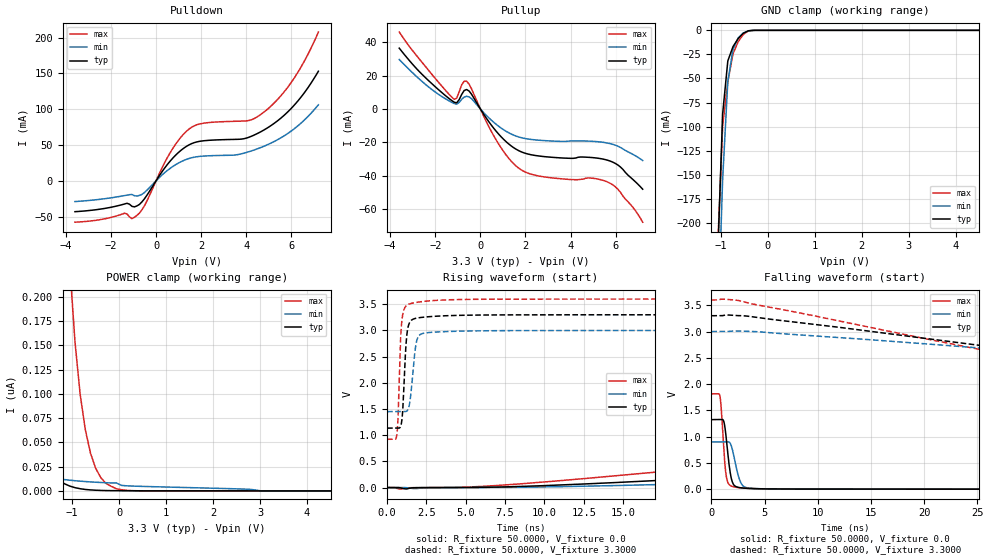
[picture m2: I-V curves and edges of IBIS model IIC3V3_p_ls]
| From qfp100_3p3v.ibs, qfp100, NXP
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[Model] IIC3V3_p_ls
|   Model IIC3V3_p_ls
| This model was characterised for following simulation conditions:
| External (pad) voltage:
|   - Typ: 3.3V,   - Min: 3.0V,   - Max: 3.6V
| Library cells for typ/min/max conditions are connected as defined below:
|  IO - External Pad
|  A - Core Input
|  EN - Output Buffer Enable
|  BOOST - vdde
|  EGP - vdd
|  EHS - gnd
|  ENZI - vdd
|  EPD - gnd
|  EPUN - vdd
|  ZI - NC
|  ZIF - NC
|  gnd - gnd
|  gnde - gnde
|  vdd - vdd
|  vdde - vdde
| All other pins connected to ground
Model_type I/O
Polarity   Non-Inverting
Enable   Active-Low
Vinl =   0.9900V
Vinh =   2.3100V
Vmeas =  1.6500V
Cref =   0.0F
Rref =   1.0000k
Vref =   0.0V
C_comp   3.6227pF   3.4779pF   3.7656pF
|C_comp_pullup   0.9287pF   0.9114pF   0.9356pF
|C_comp_pulldown   2.3426pF   2.4946pF   2.1982pF
[Model Spec]
| variable   typ   min   max
Vinh   0.9900V   0.9000V   1.0800V
Vinl   2.3100V   2.1000V   2.5200V
Vmeas   1.6500V   1.5000V   1.8000V
[Temperature Range]   25.0000   0.1250k   -40.0000
[Voltage Range]   3.3000V   3.0000V   3.6000V
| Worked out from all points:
|   slope of the pulldown table from 0 to 0.495 V, typ, clamps not added: 22 ohm
|   slope of the pullup table from 0 to 0.495 V, typ, clamps not added: 50.2 ohm
|   GND clamp passes 1 mA (typ) near -0.43 V on its own axis
|   rising waveform, R_fixture 50.0000, V_fixture 0.0: 20-80 % time 64ns typ, 78.4ns min, 50.4ns max; typ from 0 V to 1.32 V
|   rising waveform, R_fixture 50.0000, V_fixture 3.3000: 20-80 % time 227ps typ, 309ps min, 192ps max; typ from 1.14 V to 3.3 V
|   falling waveform, R_fixture 50.0000, V_fixture 0.0: 20-80 % time 465ps typ, 636ps min, 368ps max; typ from 1.32 V to 0 V
|   falling waveform, R_fixture 50.0000, V_fixture 3.3000: 20-80 % time 50.8ns typ, 68.7ns min, 38.5ns max; typ from 3.3 V to 1.14 V
[Pulldown]
|Voltage   I(typ)   I(min)   I(max)
-3.6V     -43.22mA   -29.09mA   -57.9mA
-1.29V    -31.46mA   -20.15mA   -46.47mA
-1.07V    -35.79mA   -19.19mA   -52.9mA
-850mV    -35.14mA   -21.36mA   -48.43mA
-520mV    -25.35mA   -16.52mA   -35.11mA
580mV     25.81mA    16.3mA     36.8mA
1.24V     45.79mA    28.53mA    65.82mA
1.9V      54.89mA    33.9mA     79.08mA
4.1V      60.56mA    40.39mA    84.05mA
4.76V     70.46mA    47.89mA    95.34mA
6.08V     103.9mA    71.43mA    141.2mA
7.2V      153mA      106.1mA    207.7mA
[Pullup]
|Voltage   I(typ)   I(min)   I(max)
-3.6V     36.39mA    29.61mA    46.02mA
-2.26V    16.48mA    12.77mA    22.49mA
-1.16V    4.023mA    3.267mA    5.784mA
-1.05V    3.673mA    2.839mA    6.467mA
-830mV    8.681mA    5.755mA    14.5mA
-610mV    11.63mA    7.566mA    16.61mA
710mV     -13.49mA   -9.302mA   -18.8mA
1.7V      -24.96mA   -16.76mA   -35.43mA
2.8V      -28.47mA   -18.91mA   -40.6mA
5.66V     -30.76mA   -20.46mA   -43.83mA
6.1V      -33.55mA   -22.29mA   -48.04mA
7.2V      -48.02mA   -30.86mA   -67.78mA
[GND_clamp]
|Voltage   I(typ)   I(min)   I(max)
-3.6V     -5.602A    -5.487A    -5.717A
-1.07V    -242mA     -316.8mA   -230.5mA
-960mV    -86.75mA   -154.7mA   -99.48mA
-850mV    -31.81mA   -53.08mA   -53.5mA
-740mV    -16.96mA   -19.87mA   -24.43mA
-630mV    -8.589mA   -7.919mA   -11.88mA
-520mV    -2.996mA   -2.727mA   -4.187mA
-410mV    -432.5uA   -495.8uA   -580.8uA
7.2V      0A         0A         0A
[POWER_clamp]
|Voltage   I(typ)   I(min)   I(max)
-3.6V     2.12uA     118.8nA    63.41uA
-3.03V    844.5nA    61.84nA    27.62uA
-2.37V    225.8nA    29.91nA    8.403uA
-2.04V    102.5nA    21.72nA    4.105uA
-1.82V    57.11nA    17.98nA    2.406uA
-1.49V    21.61nA    14.11nA    975.4nA
-1.05V    4.967nA    11.05nA    231.3nA
-830mV    2.261nA    10.06nA    99.54nA
-720mV    1.525nA    9.658nA    63.01nA
-500mV    718.9pA    8.985nA    23.37nA
-170mV    294.4pA    8.237nA    4.755nA
7.2V      0A         0A         0A
[Ramp]
| variable   typ   min   max
dV/dt_r  0.7941/63.9940n   0.5389/78.4223n   1.0875/50.4439n
dV/dt_f  1.2989/50.7779n   0.9297/68.6858n   1.6070/38.4858n
R_load = 50.0000
[Rising Waveform]
R_fixture= 50.0000
V_fixture= 0.0
V_fixture_min= 0.0
V_fixture_max= 0.0
|time   V(typ)   V(min)   V(max)
0s        2.243nV    52.63nV    27.54nV
860.2ps   -8.354mV   96.25uV    -30.95mV
7.694ns   14.09mV    3.106mV    53.61mV
36.07ns   426.6mV    216.4mV    777.4mV
72.53ns   857.8mV    492.3mV    1.492V
90.39ns   1.067V     599.2mV    1.672V
119.4ns   1.232V     761mV      1.77V
161.5ns   1.301V     858.8mV    1.804V
226.1ns   1.321V     892mV      1.812V
1us       1.323V     898.2mV    1.812V
[Rising Waveform]
R_fixture= 50.0000
V_fixture= 3.3000
V_fixture_min= 3.0000
V_fixture_max= 3.6000
|time   V(typ)   V(min)   V(max)
0s        1.135V     1.45V      921.7mV
623.3ps   1.135V     1.45V      1.012V
885.9ps   1.192V     1.45V      2.994V
995.6ps   1.486V     1.45V      3.308V
1.153ns   2.479V     1.449V     3.448V
1.388ns   3.122V     1.544V     3.503V
1.807ns   3.231V     2.682V     3.534V
2.03ns    3.244V     2.903V     3.544V
5.747ns   3.294V     2.993V     3.596V
1us       3.3V       3V         3.6V
[Falling Waveform]
R_fixture= 50.0000
V_fixture= 0.0
V_fixture_min= 0.0
V_fixture_max= 0.0
|time   V(typ)   V(min)   V(max)
0s        1.323V     898.3mV    1.813V
811.7ps   1.323V     898.3mV    1.764V
936.6ps   1.325V     898.3mV    1.513V
1.288ns   1.159V     898.2mV    437.6mV
1.619ns   546.6mV    900.1mV    102.8mV
2.024ns   110.5mV    713.2mV    47.69mV
2.558ns   33.4mV     237.6mV    28.48mV
2.939ns   22.04mV    70.23mV    21.07mV
5.494ns   4.545mV    4.681mV    4.711mV
1us       15.42nV    75.87nV    35.53nV
[Falling Waveform]
R_fixture= 50.0000
V_fixture= 3.3000
V_fixture_min= 3.0000
V_fixture_max= 3.6000
|time   V(typ)   V(min)   V(max)
0s        3.3V       3V         3.6V
2.441ns   3.303V     3.01V      3.594V
48.67ns   2.193V     2.354V     1.844V
54.52ns   2.077V     2.281V     1.41V
59.63ns   1.978V     2.221V     1.189V
73.24ns   1.499V     2.075V     1.003V
83.01ns   1.319V     1.96V      963mV
112.3ns   1.173V     1.577V     929mV
163.3ns   1.139V     1.467V     922.1mV
1us       1.135V     1.45V      921.7mV
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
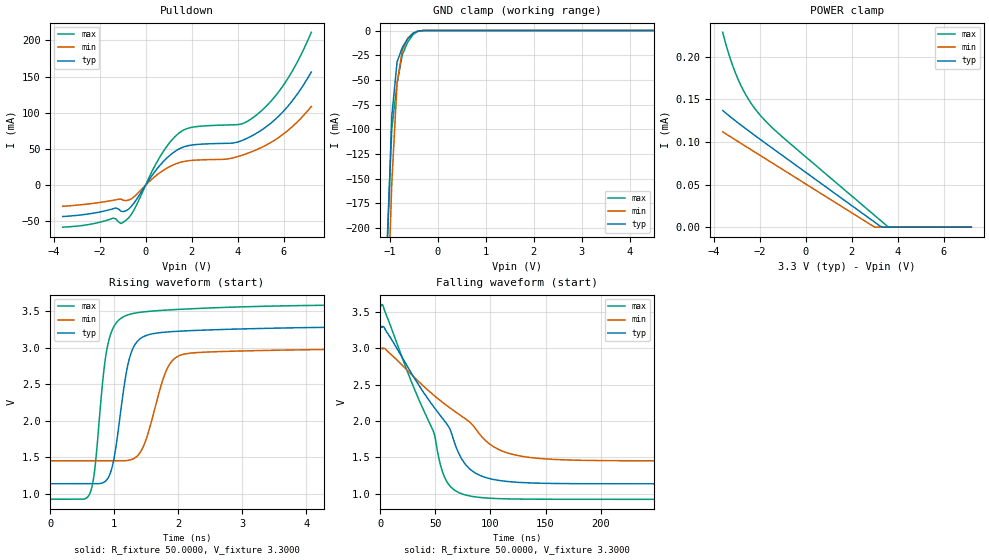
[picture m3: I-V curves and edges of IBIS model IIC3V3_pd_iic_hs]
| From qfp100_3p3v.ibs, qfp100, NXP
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[Model] IIC3V3_pd_iic_hs
|   Model IIC3V3_pd_iic_hs
| This model was characterised for following simulation conditions:
| External (pad) voltage:
|   - Typ: 3.3V,   - Min: 3.0V,   - Max: 3.6V
| Library cells for typ/min/max conditions are connected as defined below:
|  IO - External Pad
|  A - Core Input
|  EN - Output Buffer Enable
|  BOOST - vdde
|  ECS - gnd
|  EGP - gnd
|  ENZI - vdd
|  EPD - vdd
|  EPUN - vdd
|  ZI - NC
|  ZIF - NC
|  gnd - gnd
|  gnde - gnde
|  vdd - vdd
|  vdde - vdde
| All other pins connected to ground
Model_type I/O_open_drain
Polarity   Non-Inverting
Enable   Active-Low
Vinl =   0.9900V
Vinh =   2.3100V
Vmeas =  1.6500V
Cref =   0.0F
Rref =   1.0000k
Vref =   3.3000V
C_comp   3.5908pF   3.4407pF   3.7388pF
|C_comp_pullup   0.9139pF   0.9001pF   0.9174pF
|C_comp_pulldown   2.3267pF   2.4802pF   2.1806pF
[Model Spec]
| variable   typ   min   max
Vinh   0.9900V   0.9000V   1.0800V
Vinl   2.3100V   2.1000V   2.5200V
Vmeas   1.6500V   1.5000V   1.8000V
Vref   3.3000V   3.0000V   3.6000V
Cref   0.0F   0.0F   0.0F
Rref   1.0000k   1.0000k   1.0000k
[Temperature Range]   25.0000   0.1250k   -40.0000
[Voltage Range]   3.3000V   3.0000V   3.6000V
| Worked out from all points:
|   slope of the pulldown table from 0 to 0.495 V, typ, clamps not added: 22 ohm
|   GND clamp passes 1 mA (typ) near -0.43 V on its own axis
|   rising waveform, R_fixture 50.0000, V_fixture 3.3000: 20-80 % time 227ps typ, 309ps min, 193ps max; typ from 1.14 V to 3.3 V
|   falling waveform, R_fixture 50.0000, V_fixture 3.3000: 20-80 % time 50.7ns typ, 68.6ns min, 38.4ns max; typ from 3.3 V to 1.14 V
[Pulldown]
|Voltage   I(typ)   I(min)   I(max)
-3.6V     -43.22mA   -29.09mA   -57.9mA
-1.29V    -31.46mA   -20.15mA   -46.47mA
-1.07V    -35.79mA   -19.19mA   -52.9mA
-850mV    -35.14mA   -21.36mA   -48.43mA
-520mV    -25.35mA   -16.52mA   -35.11mA
580mV     25.81mA    16.3mA     36.8mA
1.24V     45.79mA    28.53mA    65.82mA
1.9V      54.89mA    33.9mA     79.08mA
4.1V      60.59mA    40.46mA    84.05mA
4.76V     70.63mA    48.16mA    95.45mA
6.08V     105.2mA    72.93mA    142.3mA
7.2V      156.3mA    108.7mA    211mA
[GND_clamp]
|Voltage   I(typ)   I(min)   I(max)
-3.6V     -5.602A    -5.487A    -5.717A
-1.07V    -242mA     -316.8mA   -230.5mA
-960mV    -86.76mA   -154.7mA   -99.49mA
-850mV    -31.82mA   -53.09mA   -53.51mA
-740mV    -16.97mA   -19.87mA   -24.44mA
-630mV    -8.597mA   -7.926mA   -11.89mA
-520mV    -3.004mA   -2.733mA   -4.196mA
-410mV    -439.7uA   -501.8uA   -589.4uA
7.2V      0A         0A         0A
[POWER_clamp]
|Voltage   I(typ)   I(min)   I(max)
-3.6V     137uA      111.9uA    228.9uA
-3.47V    134.1uA    109.7uA    215.6uA
-3.25V    129.3uA    106uA      196.2uA
-2.92V    122.3uA    100.4uA    172.9uA
-2.48V    113.3uA    92.88uA    150.2uA
-2.04V    104.5uA    85.42uA    133.7uA
-1.16V    87.2uA     70.51uA    109.7uA
2.91V     7.626uA    1.527uA    15.86uA
3.02V     5.475uA    0A         13.33uA
3.24V     1.173uA    0A         8.273uA
3.57V     0A         0A         687.1nA
7.2V      0A         0A         0A
[Ramp]
| variable   typ   min   max
dV/dt_r  1.2973/0.2266n   0.9287/0.3094n   1.6047/0.1926n
dV/dt_f  1.2973/50.7158n   0.9287/68.5865n   1.6047/38.4185n
R_load = 50.0000
[Rising Waveform]
R_fixture= 50.0000
V_fixture= 3.3000
V_fixture_min= 3.0000
V_fixture_max= 3.6000
|time   V(typ)   V(min)   V(max)
0s        1.135V     1.45V      921.3mV
627.1ps   1.134V     1.45V      1.02V
885.2ps   1.192V     1.45V      2.984V
999.3ps   1.498V     1.449V     3.302V
1.134ns   2.353V     1.449V     3.423V
1.356ns   3.086V     1.513V     3.482V
1.795ns   3.217V     2.652V     3.518V
2.027ns   3.23V      2.898V     3.53V
5.612ns   3.291V     2.989V     3.593V
1us       3.297V     2.998V     3.596V
[Falling Waveform]
R_fixture= 50.0000
V_fixture= 3.3000
V_fixture_min= 3.0000
V_fixture_max= 3.6000
|time   V(typ)   V(min)   V(max)
0s        3.297V     2.998V     3.596V
2.449ns   3.298V     2.995V     3.589V
48.58ns   2.192V     2.352V     1.841V
54.47ns   2.075V     2.279V     1.403V
59.64ns   1.974V     2.218V     1.184V
73.64ns   1.483V     2.067V     999.5mV
83.28ns   1.313V     1.951V     961.5mV
112.3ns   1.172V     1.576V     928.6mV
164ns     1.138V     1.466V     921.8mV
1us       1.135V     1.45V      921.3mV
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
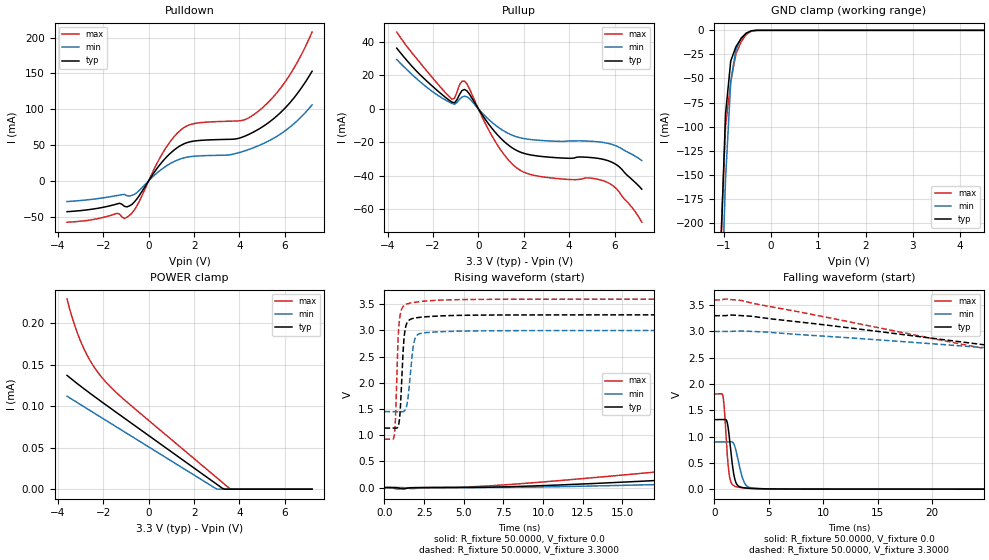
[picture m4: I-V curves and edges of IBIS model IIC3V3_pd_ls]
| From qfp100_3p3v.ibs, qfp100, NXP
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[Model] IIC3V3_pd_ls
|   Model IIC3V3_pd_ls
| This model was characterised for following simulation conditions:
| External (pad) voltage:
|   - Typ: 3.3V,   - Min: 3.0V,   - Max: 3.6V
| Library cells for typ/min/max conditions are connected as defined below:
|  IO - External Pad
|  A - Core Input
|  EN - Output Buffer Enable
|  BOOST - vdde
|  EGP - vdd
|  EHS - gnd
|  ENZI - vdd
|  EPD - vdd
|  EPUN - vdd
|  ZI - NC
|  ZIF - NC
|  gnd - gnd
|  gnde - gnde
|  vdd - vdd
|  vdde - vdde
| All other pins connected to ground
Model_type I/O
Polarity   Non-Inverting
Enable   Active-Low
Vinl =   0.9900V
Vinh =   2.3100V
Vmeas =  1.6500V
Cref =   0.0F
Rref =   1.0000k
Vref =   0.0V
C_comp   3.5907pF   3.4406pF   3.7387pF
|C_comp_pullup   0.9138pF   0.8999pF   0.9173pF
|C_comp_pulldown   2.3268pF   2.4803pF   2.1806pF
[Model Spec]
| variable   typ   min   max
Vinh   0.9900V   0.9000V   1.0800V
Vinl   2.3100V   2.1000V   2.5200V
Vmeas   1.6500V   1.5000V   1.8000V
[Temperature Range]   25.0000   0.1250k   -40.0000
[Voltage Range]   3.3000V   3.0000V   3.6000V
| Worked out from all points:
|   slope of the pulldown table from 0 to 0.495 V, typ, clamps not added: 22 ohm
|   slope of the pullup table from 0 to 0.495 V, typ, clamps not added: 50.2 ohm
|   GND clamp passes 1 mA (typ) near -0.43 V on its own axis
|   rising waveform, R_fixture 50.0000, V_fixture 0.0: 20-80 % time 64ns typ, 78.4ns min, 50.4ns max; typ from 0 V to 1.32 V
|   rising waveform, R_fixture 50.0000, V_fixture 3.3000: 20-80 % time 227ps typ, 309ps min, 192ps max; typ from 1.14 V to 3.3 V
|   falling waveform, R_fixture 50.0000, V_fixture 0.0: 20-80 % time 465ps typ, 634ps min, 367ps max; typ from 1.32 V to 0 V
|   falling waveform, R_fixture 50.0000, V_fixture 3.3000: 20-80 % time 50.8ns typ, 68.6ns min, 38.5ns max; typ from 3.3 V to 1.14 V
[Pulldown]
|Voltage   I(typ)   I(min)   I(max)
-3.6V     -43.22mA   -29.09mA   -57.9mA
-1.29V    -31.46mA   -20.15mA   -46.47mA
-1.07V    -35.79mA   -19.19mA   -52.9mA
-850mV    -35.14mA   -21.36mA   -48.43mA
-520mV    -25.35mA   -16.52mA   -35.11mA
580mV     25.81mA    16.3mA     36.8mA
1.24V     45.79mA    28.53mA    65.82mA
1.9V      54.89mA    33.9mA     79.08mA
4.1V      60.55mA    40.38mA    84.05mA
4.76V     70.44mA    47.87mA    95.32mA
6.08V     103.9mA    71.39mA    141.2mA
7.2V      152.9mA    106mA      207.6mA
[Pullup]
|Voltage   I(typ)   I(min)   I(max)
-3.6V     36.34mA    29.56mA    45.96mA
-2.26V    16.45mA    12.75mA    22.46mA
-1.16V    4.011mA    3.257mA    5.77mA
-1.05V    3.663mA    2.83mA     6.456mA
-830mV    8.674mA    5.749mA    14.49mA
-610mV    11.63mA    7.563mA    16.6mA
710mV     -13.49mA   -9.302mA   -18.8mA
1.7V      -24.96mA   -16.76mA   -35.43mA
2.8V      -28.47mA   -18.91mA   -40.6mA
5.66V     -30.76mA   -20.46mA   -43.83mA
6.1V      -33.55mA   -22.29mA   -48.04mA
7.2V      -48.02mA   -30.86mA   -67.78mA
[GND_clamp]
|Voltage   I(typ)   I(min)   I(max)
-3.6V     -5.602A    -5.487A    -5.717A
-1.07V    -242mA     -316.8mA   -230.5mA
-960mV    -86.76mA   -154.7mA   -99.49mA
-850mV    -31.82mA   -53.09mA   -53.51mA
-740mV    -16.97mA   -19.87mA   -24.44mA
-630mV    -8.597mA   -7.926mA   -11.89mA
-520mV    -3.004mA   -2.733mA   -4.196mA
-410mV    -439.7uA   -501.8uA   -589.4uA
7.2V      0A         0A         0A
[POWER_clamp]
|Voltage   I(typ)   I(min)   I(max)
-3.6V     137uA      111.9uA    228.9uA
-3.47V    134.1uA    109.7uA    215.6uA
-3.25V    129.3uA    106uA      196.2uA
-2.92V    122.3uA    100.4uA    172.9uA
-2.48V    113.3uA    92.88uA    150.2uA
-2.04V    104.5uA    85.42uA    133.7uA
-1.16V    87.2uA     70.51uA    109.7uA
2.91V     7.626uA    1.527uA    15.86uA
3.02V     5.475uA    0A         13.33uA
3.24V     1.173uA    0A         8.273uA
3.57V     0A         0A         687.1nA
7.2V      0A         0A         0A
[Ramp]
| variable   typ   min   max
dV/dt_r  0.7934/63.9635n   0.5385/78.3919n   1.0867/50.4446n
dV/dt_f  1.2983/50.7687n   0.9293/68.6224n   1.6062/38.4607n
R_load = 50.0000
[Rising Waveform]
R_fixture= 50.0000
V_fixture= 0.0
V_fixture_min= 0.0
V_fixture_max= 0.0
|time   V(typ)   V(min)   V(max)
0s        2.145nV    50.58nV    26.14nV
861.3ps   -8.453mV   96.97uV    -30.96mV
7.115ns   9.664mV    1.749mV    41.67mV
36.37ns   430.8mV    219mV      783.7mV
71.86ns   850.4mV    487.7mV    1.481V
89.51ns   1.059V     593.9mV    1.665V
118.1ns   1.228V     755.2mV    1.767V
162.1ns   1.301V     858.9mV    1.803V
227.2ns   1.32V      891.5mV    1.81V
1us       1.322V     897.5mV    1.811V
[Rising Waveform]
R_fixture= 50.0000
V_fixture= 3.3000
V_fixture_min= 3.0000
V_fixture_max= 3.6000
|time   V(typ)   V(min)   V(max)
0s        1.135V     1.45V      921.3mV
623.7ps   1.134V     1.45V      1.013V
886.3ps   1.192V     1.45V      2.995V
995.3ps   1.484V     1.449V     3.306V
1.153ns   2.478V     1.448V     3.446V
1.39ns    3.122V     1.545V     3.502V
1.808ns   3.23V      2.683V     3.532V
2.031ns   3.242V     2.902V     3.542V
5.569ns   3.291V     2.99V      3.592V
1us       3.299V     2.999V     3.598V
[Falling Waveform]
R_fixture= 50.0000
V_fixture= 0.0
V_fixture_min= 0.0
V_fixture_max= 0.0
|time   V(typ)   V(min)   V(max)
0s        1.322V     897.6mV    1.811V
803.5ps   1.322V     897.6mV    1.771V
938ps     1.323V     897.6mV    1.508V
1.29ns    1.155V     897.5mV    430.4mV
1.598ns   582.8mV    900.1mV    107.7mV
2.033ns   105.6mV    704.7mV    45.5mV
2.568ns   31.86mV    229.6mV    26.86mV
2.948ns   20.92mV    67.62mV    19.74mV
5.523ns   4.043mV    4.229mV    4.202mV
1us       15.31nV    73.81nV    34.13nV
[Falling Waveform]
R_fixture= 50.0000
V_fixture= 3.3000
V_fixture_min= 3.0000
V_fixture_max= 3.6000
|time   V(typ)   V(min)   V(max)
0s        3.299V     2.999V     3.598V
2.463ns   3.299V     3.008V     3.589V
48.43ns   2.196V     2.355V     1.851V
54.52ns   2.075V     2.279V     1.405V
59.7ns    1.974V     2.219V     1.185V
72ns      1.531V     2.085V     1.01V
83.3ns    1.314V     1.952V     961.7mV
110.8ns   1.175V     1.585V     929.2mV
168.9ns   1.137V     1.463V     921.7mV
1us       1.135V     1.45V      921.3mV
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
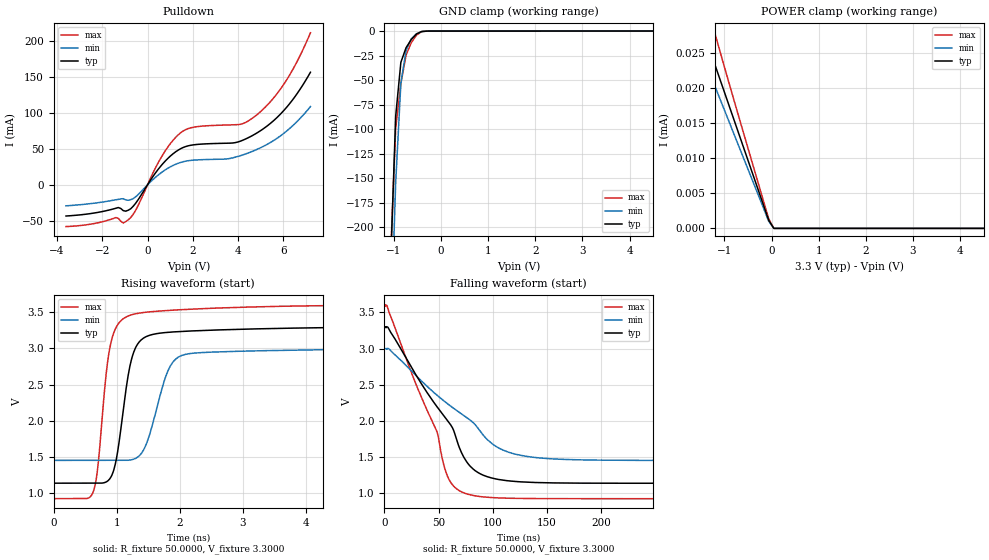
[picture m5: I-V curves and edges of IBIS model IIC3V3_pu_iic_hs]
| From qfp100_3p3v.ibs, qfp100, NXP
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[Model] IIC3V3_pu_iic_hs
|   Model IIC3V3_pu_iic_hs
| This model was characterised for following simulation conditions:
| External (pad) voltage:
|   - Typ: 3.3V,   - Min: 3.0V,   - Max: 3.6V
| Library cells for typ/min/max conditions are connected as defined below:
|  IO - External Pad
|  A - Core Input
|  EN - Output Buffer Enable
|  BOOST - vdde
|  ECS - gnd
|  EGP - gnd
|  ENZI - vdd
|  EPD - gnd
|  EPUN - gnd
|  ZI - NC
|  ZIF - NC
|  gnd - gnd
|  gnde - gnde
|  vdd - vdd
|  vdde - vdde
| All other pins connected to ground
Model_type I/O_open_drain
Polarity   Non-Inverting
Enable   Active-Low
Vinl =   0.9900V
Vinh =   2.3100V
Vmeas =  1.6500V
Cref =   0.0F
Rref =   1.0000k
Vref =   3.3000V
C_comp   3.5868pF   3.4363pF   3.7354pF
|C_comp_pullup   0.9046pF   0.8911pF   0.9077pF
|C_comp_pulldown   2.3321pF   2.4858pF   2.1859pF
[Model Spec]
| variable   typ   min   max
Vinh   0.9900V   0.9000V   1.0800V
Vinl   2.3100V   2.1000V   2.5200V
Vmeas   1.6500V   1.5000V   1.8000V
Vref   3.3000V   3.0000V   3.6000V
Cref   0.0F   0.0F   0.0F
Rref   1.0000k   1.0000k   1.0000k
[Temperature Range]   25.0000   0.1250k   -40.0000
[Voltage Range]   3.3000V   3.0000V   3.6000V
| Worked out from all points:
|   slope of the pulldown table from 0 to 0.495 V, typ, clamps not added: 22 ohm
|   GND clamp passes 1 mA (typ) near -0.43 V on its own axis
|   rising waveform, R_fixture 50.0000, V_fixture 3.3000: 20-80 % time 227ps typ, 309ps min, 193ps max; typ from 1.14 V to 3.3 V
|   falling waveform, R_fixture 50.0000, V_fixture 3.3000: 20-80 % time 50.8ns typ, 68.7ns min, 38.5ns max; typ from 3.3 V to 1.14 V
[Pulldown]
|Voltage   I(typ)   I(min)   I(max)
-3.6V     -43.22mA   -29.09mA   -57.9mA
-1.29V    -31.46mA   -20.15mA   -46.47mA
-1.07V    -35.79mA   -19.19mA   -52.9mA
-850mV    -35.14mA   -21.36mA   -48.43mA
-520mV    -25.35mA   -16.52mA   -35.11mA
580mV     25.81mA    16.3mA     36.8mA
1.24V     45.79mA    28.53mA    65.82mA
1.9V      54.89mA    33.9mA     79.08mA
4.1V      60.59mA    40.46mA    84.05mA
4.76V     70.63mA    48.16mA    95.45mA
6.08V     105.2mA    72.93mA    142.3mA
7.2V      156.3mA    108.7mA    211mA
[GND_clamp]
|Voltage   I(typ)   I(min)   I(max)
-3.6V     -5.602A    -5.487A    -5.717A
-1.07V    -242.1mA   -316.8mA   -230.6mA
-960mV    -86.82mA   -154.8mA   -99.57mA
-850mV    -31.89mA   -53.14mA   -53.6mA
-740mV    -17.03mA   -19.92mA   -24.52mA
-630mV    -8.661mA   -7.977mA   -11.97mA
-520mV    -3.068mA   -2.784mA   -4.278mA
-410mV    -504.1uA   -552.6uA   -671.9uA
7.2V      0A         0A         0A
[POWER_clamp]
|Voltage   I(typ)   I(min)   I(max)
-3.6V     71.92uA    60.65uA    145.6uA
-1.71V    33.28uA    28.87uA    40.89uA
-1.6V     31.13uA    27.02uA    37.92uA
-1.49V    28.99uA    25.16uA    35.04uA
-1.38V    26.85uA    23.31uA    32.26uA
-1.27V    24.71uA    21.46uA    29.54uA
-1.16V    22.58uA    19.61uA    26.88uA
-720mV    14.02uA    12.19uA    16.54uA
-60mV     1.171uA    1.025uA    1.377uA
50mV      0A         0A         0A
7.2V      0A         0A         0A
[Ramp]
| variable   typ   min   max
dV/dt_r  1.2984/0.2267n   0.9292/0.3093n   1.6064/0.1926n
dV/dt_f  1.2984/50.7672n   0.9292/68.6924n   1.6064/38.4880n
R_load = 50.0000
[Rising Waveform]
R_fixture= 50.0000
V_fixture= 3.3000
V_fixture_min= 3.0000
V_fixture_max= 3.6000
|time   V(typ)   V(min)   V(max)
0s        1.136V     1.451V     922.6mV
627.5ps   1.136V     1.451V     1.022V
886.2ps   1.194V     1.451V     2.993V
998.1ps   1.495V     1.451V     3.304V
1.136ns   2.371V     1.451V     3.429V
1.355ns   3.088V     1.514V     3.487V
1.817ns   3.222V     2.7V       3.524V
2.026ns   3.233V     2.9V       3.534V
5.582ns   3.295V     2.992V     3.597V
1us       3.3V       3V         3.6V
[Falling Waveform]
R_fixture= 50.0000
V_fixture= 3.3000
V_fixture_min= 3.0000
V_fixture_max= 3.6000
|time   V(typ)   V(min)   V(max)
0s        3.3V       3V         3.6V
2.455ns   3.301V     2.998V     3.592V
48.62ns   2.194V     2.354V     1.844V
54.53ns   2.076V     2.281V     1.406V
59.7ns    1.976V     2.22V      1.187V
73.1ns    1.502V     2.076V     1.004V
83.3ns    1.316V     1.955V     963.1mV
112.3ns   1.173V     1.578V     929.9mV
163.5ns   1.14V      1.468V     923.1mV
1us       1.136V     1.451V     922.6mV
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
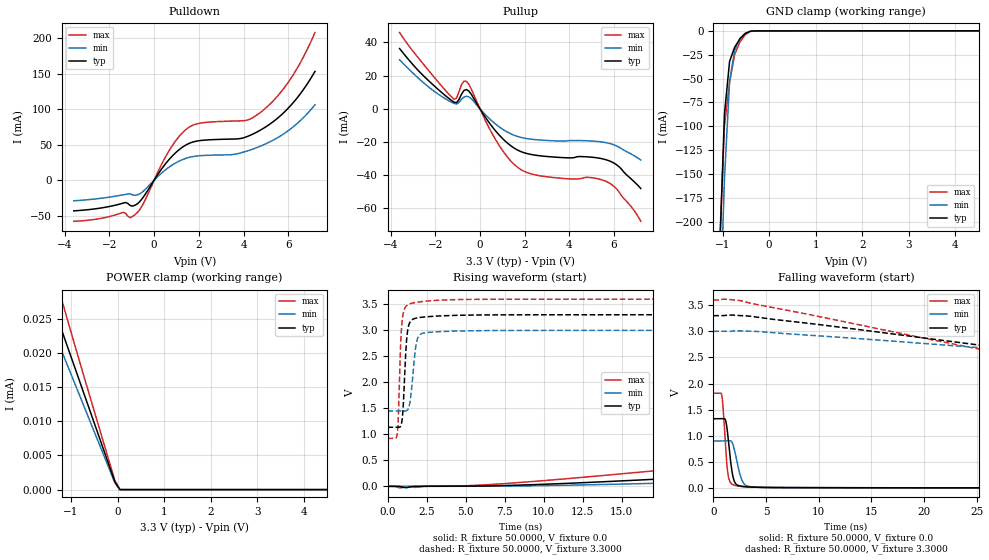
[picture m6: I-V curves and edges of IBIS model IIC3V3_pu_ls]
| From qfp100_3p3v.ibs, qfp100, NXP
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[Model] IIC3V3_pu_ls
|   Model IIC3V3_pu_ls
| This model was characterised for following simulation conditions:
| External (pad) voltage:
|   - Typ: 3.3V,   - Min: 3.0V,   - Max: 3.6V
| Library cells for typ/min/max conditions are connected as defined below:
|  IO - External Pad
|  A - Core Input
|  EN - Output Buffer Enable
|  BOOST - vdde
|  EGP - vdd
|  EHS - gnd
|  ENZI - vdd
|  EPD - gnd
|  EPUN - gnd
|  ZI - NC
|  ZIF - NC
|  gnd - gnd
|  gnde - gnde
|  vdd - vdd
|  vdde - vdde
| All other pins connected to ground
Model_type I/O
Polarity   Non-Inverting
Enable   Active-Low
Vinl =   0.9900V
Vinh =   2.3100V
Vmeas =  1.6500V
Cref =   0.0F
Rref =   1.0000k
Vref =   0.0V
C_comp   3.5867pF   3.4362pF   3.7352pF
|C_comp_pullup   0.9044pF   0.8908pF   0.9076pF
|C_comp_pulldown   2.3321pF   2.4859pF   2.1859pF
[Model Spec]
| variable   typ   min   max
Vinh   0.9900V   0.9000V   1.0800V
Vinl   2.3100V   2.1000V   2.5200V
Vmeas   1.6500V   1.5000V   1.8000V
[Temperature Range]   25.0000   0.1250k   -40.0000
[Voltage Range]   3.3000V   3.0000V   3.6000V
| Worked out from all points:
|   slope of the pulldown table from 0 to 0.495 V, typ, clamps not added: 22 ohm
|   slope of the pullup table from 0 to 0.495 V, typ, clamps not added: 50.2 ohm
|   GND clamp passes 1 mA (typ) near -0.43 V on its own axis
|   rising waveform, R_fixture 50.0000, V_fixture 0.0: 20-80 % time 64ns typ, 78.4ns min, 50.4ns max; typ from 0.001 V to 1.32 V
|   rising waveform, R_fixture 50.0000, V_fixture 3.3000: 20-80 % time 227ps typ, 309ps min, 192ps max; typ from 1.14 V to 3.3 V
|   falling waveform, R_fixture 50.0000, V_fixture 0.0: 20-80 % time 466ps typ, 636ps min, 368ps max; typ from 1.32 V to 0.001 V
|   falling waveform, R_fixture 50.0000, V_fixture 3.3000: 20-80 % time 50.8ns typ, 68.7ns min, 38.5ns max; typ from 3.3 V to 1.14 V
[Pulldown]
|Voltage   I(typ)   I(min)   I(max)
-3.6V     -43.22mA   -29.09mA   -57.9mA
-1.29V    -31.46mA   -20.15mA   -46.47mA
-1.07V    -35.79mA   -19.19mA   -52.9mA
-850mV    -35.14mA   -21.36mA   -48.43mA
-520mV    -25.35mA   -16.52mA   -35.11mA
580mV     25.81mA    16.3mA     36.8mA
1.24V     45.79mA    28.53mA    65.82mA
1.9V      54.89mA    33.9mA     79.08mA
4.1V      60.55mA    40.38mA    84.05mA
4.76V     70.44mA    47.87mA    95.32mA
6.08V     103.9mA    71.39mA    141.2mA
7.2V      152.9mA    106mA      207.6mA
[Pullup]
|Voltage   I(typ)   I(min)   I(max)
-3.6V     36.34mA    29.56mA    45.96mA
-2.26V    16.45mA    12.75mA    22.46mA
-1.16V    4.011mA    3.257mA    5.77mA
-1.05V    3.663mA    2.83mA     6.455mA
-830mV    8.673mA    5.749mA    14.49mA
-610mV    11.63mA    7.563mA    16.6mA
710mV     -13.49mA   -9.302mA   -18.8mA
1.7V      -24.96mA   -16.76mA   -35.43mA
2.8V      -28.47mA   -18.91mA   -40.6mA
5.66V     -30.76mA   -20.46mA   -43.83mA
6.1V      -33.55mA   -22.29mA   -48.04mA
7.2V      -48.02mA   -30.86mA   -67.78mA
[GND_clamp]
|Voltage   I(typ)   I(min)   I(max)
-3.6V     -5.602A    -5.487A    -5.717A
-1.07V    -242.1mA   -316.8mA   -230.6mA
-960mV    -86.82mA   -154.8mA   -99.57mA
-850mV    -31.89mA   -53.14mA   -53.6mA
-740mV    -17.03mA   -19.92mA   -24.52mA
-630mV    -8.661mA   -7.977mA   -11.97mA
-520mV    -3.068mA   -2.784mA   -4.278mA
-410mV    -504.1uA   -552.6uA   -671.9uA
7.2V      0A         0A         0A
[POWER_clamp]
|Voltage   I(typ)   I(min)   I(max)
-3.6V     71.92uA    60.65uA    145.6uA
-1.71V    33.28uA    28.87uA    40.89uA
-1.6V     31.13uA    27.02uA    37.92uA
-1.49V    28.99uA    25.16uA    35.04uA
-1.38V    26.85uA    23.31uA    32.26uA
-1.27V    24.71uA    21.46uA    29.54uA
-1.16V    22.58uA    19.61uA    26.88uA
-720mV    14.02uA    12.19uA    16.54uA
-60mV     1.171uA    1.025uA    1.377uA
50mV      0A         0A         0A
7.2V      0A         0A         0A
[Ramp]
| variable   typ   min   max
dV/dt_r  0.7945/63.9693n   0.5393/78.3973n   1.0878/50.4118n
dV/dt_f  1.2984/50.8047n   0.9292/68.6852n   1.6064/38.4897n
R_load = 50.0000
[Rising Waveform]
R_fixture= 50.0000
V_fixture= 0.0
V_fixture_min= 0.0
V_fixture_max= 0.0
|time   V(typ)   V(min)   V(max)
0s        903.5uV    965.2uV    889.6uV
860.3ps   -7.442mV   1.061mV    -28.62mV
7.683ns   17.11mV    5.617mV    57.12mV
36.03ns   428.9mV    218.5mV    780mV
72.51ns   860.4mV    494.4mV    1.495V
90.37ns   1.07V      601.4mV    1.674V
119.5ns   1.235V     763.7mV    1.772V
161.2ns   1.303V     860.2mV    1.806V
225.5ns   1.322V     893.6mV    1.813V
1us       1.325V     899.8mV    1.814V
[Rising Waveform]
R_fixture= 50.0000
V_fixture= 3.3000
V_fixture_min= 3.0000
V_fixture_max= 3.6000
|time   V(typ)   V(min)   V(max)
0s        1.136V     1.451V     922.6mV
623.3ps   1.136V     1.451V     1.014V
885.9ps   1.194V     1.451V     2.997V
995.6ps   1.488V     1.45V      3.311V
1.152ns   2.479V     1.45V      3.45V
1.388ns   3.124V     1.545V     3.506V
1.806ns   3.233V     2.682V     3.536V
2.029ns   3.245V     2.904V     3.546V
5.588ns   3.294V     2.993V     3.596V
1us       3.3V       3V         3.6V
[Falling Waveform]
R_fixture= 50.0000
V_fixture= 0.0
V_fixture_min= 0.0
V_fixture_max= 0.0
|time   V(typ)   V(min)   V(max)
0s        1.325V     899.9mV    1.814V
811.5ps   1.325V     899.9mV    1.766V
936.9ps   1.326V     899.9mV    1.514V
1.288ns   1.161V     899.8mV    439mV
1.62ns    546.3mV    901.6mV    104.6mV
2.025ns   112.1mV    714.3mV    50.05mV
2.556ns   35.58mV    240.3mV    31.23mV
2.938ns   24.31mV    72.31mV    24mV
5.516ns   7.277mV    6.772mV    8.332mV
1us       903.6uV    965.2uV    889.6uV
[Falling Waveform]
R_fixture= 50.0000
V_fixture= 3.3000
V_fixture_min= 3.0000
V_fixture_max= 3.6000
|time   V(typ)   V(min)   V(max)
0s        3.3V       3V         3.6V
2.451ns   3.303V     3.01V      3.593V
48.64ns   2.195V     2.355V     1.846V
54.55ns   2.078V     2.281V     1.409V
59.7ns    1.977V     2.221V     1.188V
73.96ns   1.48V      2.067V     1V
83.22ns   1.318V     1.957V     963.5mV
110.3ns   1.177V     1.591V     930.7mV
164.3ns   1.14V      1.467V     923.1mV
1us       1.136V     1.451V     922.6mV
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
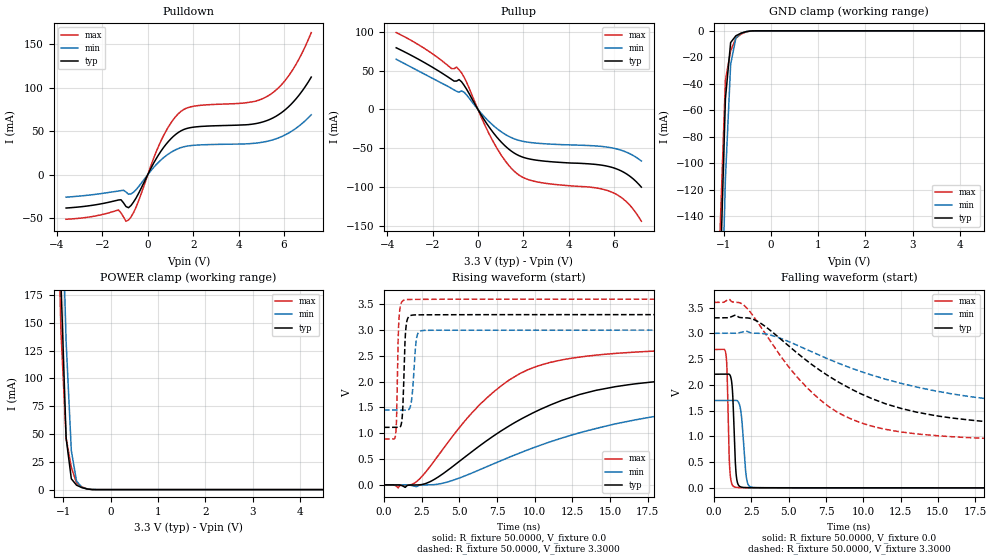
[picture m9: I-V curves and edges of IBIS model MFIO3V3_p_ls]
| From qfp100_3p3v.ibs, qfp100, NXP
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[Model] MFIO3V3_p_ls
|   Model MFIO3V3_p_ls
| This model was characterised for following simulation conditions:
| External (pad) voltage:
|   - Typ: 3.3V,   - Min: 3.0V,   - Max: 3.6V
| Library cells for typ/min/max conditions are connected as defined below:
|  IO - External Pad
|  A - Core Input
|  EN - Output Buffer Enable
|  BOOST - vdde
|  EHS - gnd
|  ENZI - vdd
|  EPD - gnd
|  EPUN - vdd
|  ZI - NC
|  ZIF - NC
|  gnd - gnd
|  gnde - gnde
|  vdd - vdd
|  vdde - vdde
| All other pins connected to ground
Model_type I/O
Polarity   Non-Inverting
Enable   Active-Low
Vinl =   0.9900V
Vinh =   2.3100V
Vmeas =  1.6500V
Cref =   0.0F
Rref =   100.0000
Vref =   0.0V
C_comp   1.5616pF   1.4857pF   1.6280pF
|C_comp_pullup   0.7424pF   0.7664pF   0.7060pF
|C_comp_pulldown   0.6045pF   0.6430pF   0.5687pF
[Model Spec]
| variable   typ   min   max
Vinh   0.9900V   0.9000V   1.0800V
Vinl   2.3100V   2.1000V   2.5200V
Vmeas   1.6500V   1.5000V   1.8000V
[Temperature Range]   25.0000   0.1250k   -40.0000
[Voltage Range]   3.3000V   3.0000V   3.6000V
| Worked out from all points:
|   slope of the pulldown table from 0 to 0.495 V, typ, clamps not added: 21 ohm
|   slope of the pullup table from 0 to 0.495 V, typ, clamps not added: 21.7 ohm
|   GND clamp passes 1 mA (typ) near -0.56 V on its own axis
|   POWER clamp passes 1 mA (typ) near -0.54 V on its own axis
|   rising waveform, R_fixture 50.0000, V_fixture 0.0: 20-80 % time 8.22ns typ, 11.9ns min, 5.44ns max; typ from 0 V to 2.21 V
|   rising waveform, R_fixture 50.0000, V_fixture 3.3000: 20-80 % time 151ps typ, 221ps min, 120ps max; typ from 1.11 V to 3.3 V
|   falling waveform, R_fixture 50.0000, V_fixture 0.0: 20-80 % time 179ps typ, 263ps min, 139ps max; typ from 2.21 V to 0 V
|   falling waveform, R_fixture 50.0000, V_fixture 3.3000: 20-80 % time 7.84ns typ, 11.2ns min, 5.22ns max; typ from 3.3 V to 1.11 V
[Pulldown]
|Voltage   I(typ)   I(min)   I(max)
-3.6V     -38.54mA   -26.03mA   -51.47mA
-1.29V    -29.27mA   -18.96mA   -40.78mA
-960mV    -36.81mA   -20.01mA   -53.83mA
-850mV    -38.18mA   -22.68mA   -52.4mA
-520mV    -27.12mA   -17.5mA    -37.74mA
580mV     26.98mA    16.83mA    38.78mA
1.35V     48.62mA    30.01mA    70.27mA
2.01V     54.62mA    33.69mA    78.71mA
4.43V     57.57mA    35.54mA    83.11mA
5.31V     62.85mA    38.64mA    90.87mA
6.3V      80.67mA    49.35mA    117.4mA
7.2V      112.3mA    68.85mA    163.6mA
[Pullup]
|Voltage   I(typ)   I(min)   I(max)
-3.6V     79.43mA    64.59mA    99.03mA
-1.05V    36.46mA    25.05mA    52.51mA
-830mV    38.41mA    22.29mA    50.98mA
-610mV    31.13mA    22.16mA    41.54mA
270mV     -13.03mA   -9.075mA   -18mA
710mV     -31.29mA   -21.6mA    -43.53mA
1.26V     -48.73mA   -33.16mA   -68.54mA
1.7V      -58.01mA   -38.97mA   -82.27mA
2.58V     -65.44mA   -43.49mA   -93.28mA
5.88V     -74.5mA    -49.46mA   -106.4mA
6.65V     -85.19mA   -56.54mA   -122.1mA
7.2V      -100.2mA   -66.51mA   -144.2mA
[GND_clamp]
|Voltage   I(typ)   I(min)   I(max)
-3.6V     -4.776A    -4.755A    -4.803A
-1.07V    -185.2mA   -255.7mA   -147.9mA
-960mV    -51.25mA   -111.8mA   -37.35mA
-850mV    -8.87mA    -25.44mA   -15.18mA
-740mV    -3.773mA   -5.524mA   -5.635mA
-630mV    -1.795mA   -1.776mA   -2.434mA
-520mV    -584uA     -575.7uA   -771.5uA
-300mV    -2.698uA   -7.245uA   -2.257uA
7.2V      0A         0A         0A
[POWER_clamp]
|Voltage   I(typ)   I(min)   I(max)
-3.6V     5.691A     5.665A     5.731A
-1.16V    387.4mA    485.6mA    339.2mA
-1.05V    187.8mA    295.9mA    142.7mA
-940mV    46.35mA    133mA      46.17mA
-830mV    9.704mA    34.97mA    20.11mA
-720mV    3.968mA    7.718mA    5.953mA
-610mV    1.842mA    2.02mA     2.519mA
-500mV    572.5uA    622.5uA    738.7uA
-280mV    1.642uA    8.962uA    609.4nA
7.2V      0A         0A         0A
[Ramp]
| variable   typ   min   max
dV/dt_r  1.3235/8.2159n   1.0168/11.9497n   1.6117/5.4435n
dV/dt_f  1.3111/7.8398n   0.9293/11.2433n   1.6259/5.2206n
R_load = 50.0000
[Rising Waveform]
R_fixture= 50.0000
V_fixture= 0.0
V_fixture_min= 0.0
V_fixture_max= 0.0
|time   V(typ)   V(min)   V(max)
0s        3.928nV    110.6nV    42.16nV
944.3ps   303.8uV    -23.2uV    -57.73mV
2.146ns   -2.039mV   -34.37mV   58.41mV
3.495ns   133.1mV    9.992mV    526.1mV
6.077ns   697.8mV    259.2mV    1.472V
9.002ns   1.26V      617.8mV    2.155V
14.55ns   1.86V      1.128V     2.529V
22.08ns   2.082V     1.469V     2.634V
32.86ns   2.167V     1.616V     2.672V
100ns     2.206V     1.695V     2.686V
[Rising Waveform]
R_fixture= 50.0000
V_fixture= 3.3000
V_fixture_min= 3.0000
V_fixture_max= 3.6000
|time   V(typ)   V(min)   V(max)
0s        1.115V     1.451V     890.2mV
777.6ps   1.115V     1.451V     983mV
840ps     1.115V     1.451V     1.326V
976ps     1.113V     1.451V     3.104V
1.156ns   1.186V     1.451V     3.531V
1.489ns   3.123V     1.449V     3.591V
1.817ns   3.287V     1.61V      3.595V
2.18ns    3.295V     2.869V     3.594V
2.695ns   3.296V     2.995V     3.596V
100ns     3.3V       3V         3.6V
[Falling Waveform]
R_fixture= 50.0000
V_fixture= 0.0
V_fixture_min= 0.0
V_fixture_max= 0.0
|time   V(typ)   V(min)   V(max)
0s        2.206V     1.695V     2.686V
799.7ps   2.206V     1.695V     2.587V
879ps     2.207V     1.695V     2.185V
1.024ns   2.203V     1.695V     514.9mV
1.141ns   2.123V     1.695V     127.1mV
1.537ns   139.1mV    1.694V     7.96mV
1.822ns   14.21mV    1.428V     4.505mV
2.208ns   3.937mV    131.5mV    4.044mV
2.678ns   3.293mV    5.839mV    2.578mV
100ns     23.82nV    183.3nV    47.97nV
[Falling Waveform]
R_fixture= 50.0000
V_fixture= 3.3000
V_fixture_min= 3.0000
V_fixture_max= 3.6000
|time   V(typ)   V(min)   V(max)
0s        3.3V       3V         3.6V
2.052ns   3.301V     3.037V     3.532V
3.178ns   3.184V     2.997V     3.103V
5.581ns   2.615V     2.767V     2.145V
8.204ns   2.076V     2.435V     1.479V
10.7ns    1.718V     2.177V     1.188V
13.89ns   1.452V     1.938V     1.038V
21.03ns   1.233V     1.651V     936.3mV
32.1ns    1.147V     1.515V     900.4mV
100ns     1.115V     1.451V     890.2mV
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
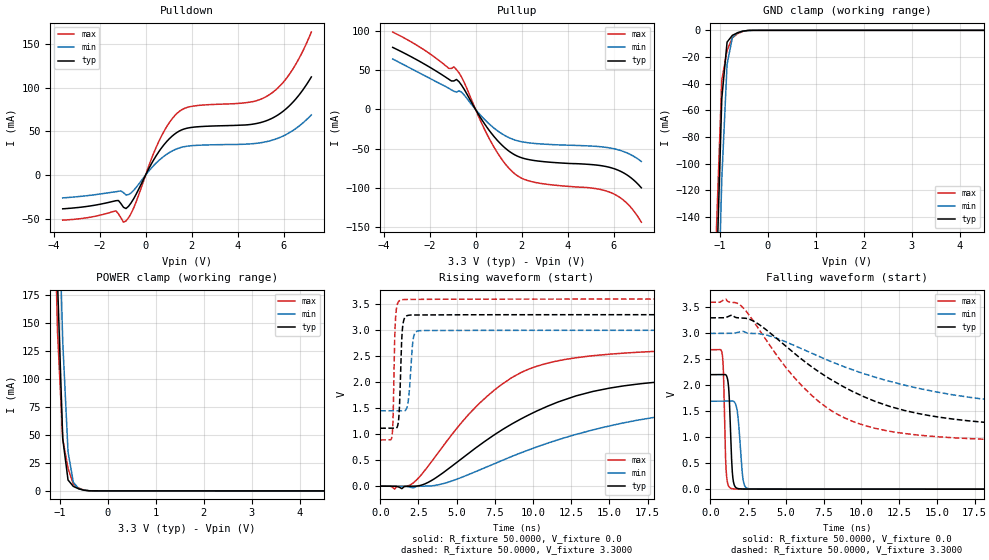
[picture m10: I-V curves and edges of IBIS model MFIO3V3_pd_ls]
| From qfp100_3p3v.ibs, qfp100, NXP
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[Model] MFIO3V3_pd_ls
|   Model MFIO3V3_pd_ls
| This model was characterised for following simulation conditions:
| External (pad) voltage:
|   - Typ: 3.3V,   - Min: 3.0V,   - Max: 3.6V
| Library cells for typ/min/max conditions are connected as defined below:
|  IO - External Pad
|  A - Core Input
|  EN - Output Buffer Enable
|  BOOST - vdde
|  EHS - gnd
|  ENZI - vdd
|  EPD - vdd
|  EPUN - vdd
|  ZI - NC
|  ZIF - NC
|  gnd - gnd
|  gnde - gnde
|  vdd - vdd
|  vdde - vdde
| All other pins connected to ground
Model_type I/O
Polarity   Non-Inverting
Enable   Active-Low
Vinl =   0.9900V
Vinh =   2.3100V
Vmeas =  1.6500V
Cref =   0.0F
Rref =   100.0000
Vref =   0.0V
C_comp   1.5343pF   1.4580pF   1.6019pF
|C_comp_pullup   0.7283pF   0.7532pF   0.6914pF
|C_comp_pulldown   0.5932pF   0.6316pF   0.5575pF
[Model Spec]
| variable   typ   min   max
Vinh   0.9900V   0.9000V   1.0800V
Vinl   2.3100V   2.1000V   2.5200V
Vmeas   1.6500V   1.5000V   1.8000V
[Temperature Range]   25.0000   0.1250k   -40.0000
[Voltage Range]   3.3000V   3.0000V   3.6000V
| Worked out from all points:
|   slope of the pulldown table from 0 to 0.495 V, typ, clamps not added: 21 ohm
|   slope of the pullup table from 0 to 0.495 V, typ, clamps not added: 21.7 ohm
|   GND clamp passes 1 mA (typ) near -0.56 V on its own axis
|   POWER clamp passes 1 mA (typ) near -0.53 V on its own axis
|   rising waveform, R_fixture 50.0000, V_fixture 0.0: 20-80 % time 8.23ns typ, 12ns min, 5.46ns max; typ from 0 V to 2.21 V
|   rising waveform, R_fixture 50.0000, V_fixture 3.3000: 20-80 % time 151ps typ, 221ps min, 120ps max; typ from 1.11 V to 3.3 V
|   falling waveform, R_fixture 50.0000, V_fixture 0.0: 20-80 % time 179ps typ, 263ps min, 138ps max; typ from 2.21 V to 0 V
|   falling waveform, R_fixture 50.0000, V_fixture 3.3000: 20-80 % time 7.85ns typ, 11.2ns min, 5.22ns max; typ from 3.3 V to 1.11 V
[Pulldown]
|Voltage   I(typ)   I(min)   I(max)
-3.6V     -38.54mA   -26.03mA   -51.47mA
-1.29V    -29.27mA   -18.96mA   -40.78mA
-960mV    -36.81mA   -20.01mA   -53.83mA
-850mV    -38.18mA   -22.68mA   -52.4mA
-520mV    -27.12mA   -17.5mA    -37.74mA
580mV     26.98mA    16.83mA    38.78mA
1.35V     48.62mA    30.01mA    70.27mA
2.01V     54.62mA    33.69mA    78.71mA
4.43V     57.57mA    35.54mA    83.11mA
5.31V     62.85mA    38.63mA    90.87mA
6.3V      80.67mA    49.35mA    117.4mA
7.2V      112.3mA    68.85mA    163.6mA
[Pullup]
|Voltage   I(typ)   I(min)   I(max)
-3.6V     79.43mA    64.59mA    99.03mA
-1.05V    36.46mA    25.05mA    52.51mA
-830mV    38.41mA    22.29mA    50.98mA
-610mV    31.13mA    22.16mA    41.54mA
270mV     -13.03mA   -9.075mA   -18mA
710mV     -31.29mA   -21.6mA    -43.53mA
1.26V     -48.73mA   -33.16mA   -68.54mA
1.7V      -58.01mA   -38.97mA   -82.27mA
2.58V     -65.44mA   -43.49mA   -93.28mA
5.88V     -74.5mA    -49.46mA   -106.4mA
6.65V     -85.19mA   -56.54mA   -122.1mA
7.2V      -100.2mA   -66.51mA   -144.2mA
[GND_clamp]
|Voltage   I(typ)   I(min)   I(max)
-3.6V     -4.776A    -4.755A    -4.803A
-1.07V    -185.2mA   -255.8mA   -147.9mA
-960mV    -51.26mA   -111.8mA   -37.36mA
-850mV    -8.879mA   -25.45mA   -15.19mA
-740mV    -3.782mA   -5.531mA   -5.645mA
-630mV    -1.803mA   -1.784mA   -2.444mA
-520mV    -592.1uA   -582.6uA   -781uA
-300mV    -8.619uA   -12.3uA    -9.227uA
7.2V      0A         0A         0A
[POWER_clamp]
|Voltage   I(typ)   I(min)   I(max)
-3.6V     5.691A     5.665A     5.731A
-1.16V    387.4mA    485.6mA    339.3mA
-1.05V    187.9mA    295.9mA    142.8mA
-940mV    46.42mA    133mA      46.27mA
-830mV    9.779mA    35.03mA    20.21mA
-720mV    4.043mA    7.776mA    6.047mA
-610mV    1.916mA    2.078mA    2.613mA
-500mV    646.2uA    680.9uA    832.2uA
-280mV    73uA       65.71uA    91.35uA
7.2V      0A         0A         0A
[Ramp]
| variable   typ   min   max
dV/dt_r  1.3230/8.2330n   1.0163/11.9606n   1.6111/5.4610n
dV/dt_f  1.3109/7.8532n   0.9293/11.2282n   1.6255/5.2173n
R_load = 50.0000
[Rising Waveform]
R_fixture= 50.0000
V_fixture= 0.0
V_fixture_min= 0.0
V_fixture_max= 0.0
|time   V(typ)   V(min)   V(max)
0s        3.835nV    108.6nV    40.83nV
2.189ns   -1.9mV     -31.34mV   68.31mV
3.468ns   128.1mV    9.002mV    515.1mV
5.854ns   648.2mV    231.8mV    1.401V
8.596ns   1.194V     570mV      2.086V
11.11ns   1.556V     842.1mV    2.378V
14.65ns   1.864V     1.134V     2.53V
22.3ns    2.084V     1.474V     2.634V
33.19ns   2.167V     1.617V     2.672V
100ns     2.205V     1.694V     2.685V
[Rising Waveform]
R_fixture= 50.0000
V_fixture= 3.3000
V_fixture_min= 3.0000
V_fixture_max= 3.6000
|time   V(typ)   V(min)   V(max)
0s        1.114V     1.45V      889.8mV
778.8ps   1.114V     1.45V      985.5mV
840.9ps   1.114V     1.45V      1.335V
969.4ps   1.113V     1.45V      3.059V
1.148ns   1.174V     1.45V      3.525V
1.484ns   3.113V     1.448V     3.589V
1.819ns   3.286V     1.613V     3.592V
2.181ns   3.293V     2.87V      3.592V
2.703ns   3.294V     2.993V     3.593V
100ns     3.299V     2.999V     3.599V
[Falling Waveform]
R_fixture= 50.0000
V_fixture= 0.0
V_fixture_min= 0.0
V_fixture_max= 0.0
|time   V(typ)   V(min)   V(max)
0s        2.205V     1.694V     2.685V
800.6ps   2.205V     1.694V     2.584V
879.8ps   2.206V     1.694V     2.176V
1.012ns   2.204V     1.694V     600.5mV
1.14ns    2.124V     1.694V     126mV
1.54ns    133mV      1.693V     5.644mV
1.825ns   12.18mV    1.417V     2.735mV
2.188ns   2.625mV    159.3mV    2.899mV
2.692ns   2.274mV    4.458mV    1.974mV
100ns     23.69nV    181.1nV    46.63nV
[Falling Waveform]
R_fixture= 50.0000
V_fixture= 3.3000
V_fixture_min= 3.0000
V_fixture_max= 3.6000
|time   V(typ)   V(min)   V(max)
0s        3.299V     2.999V     3.599V
2.055ns   3.298V     3.035V     3.527V
3.217ns   3.174V     2.994V     3.082V
5.611ns   2.604V     2.76V      2.132V
7.837ns   2.137V     2.476V     1.544V
10.33ns   1.761V     2.209V     1.217V
14.15ns   1.436V     1.92V      1.03V
21.25ns   1.229V     1.645V     934.4mV
32.49ns   1.145V     1.511V     899.6mV
100ns     1.114V     1.45V      889.8mV
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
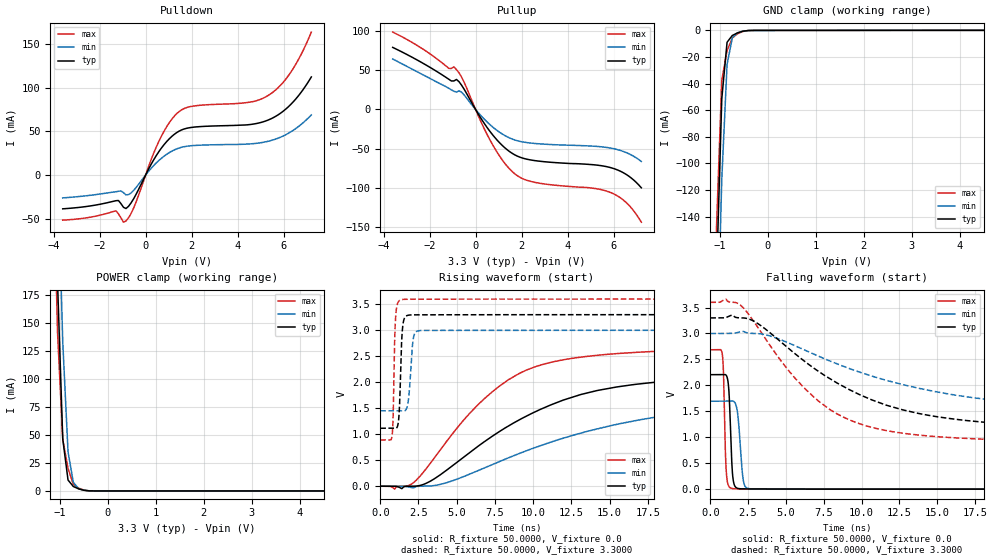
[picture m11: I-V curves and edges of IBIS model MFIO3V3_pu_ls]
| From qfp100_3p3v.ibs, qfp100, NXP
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[Model] MFIO3V3_pu_ls
|   Model MFIO3V3_pu_ls
| This model was characterised for following simulation conditions:
| External (pad) voltage:
|   - Typ: 3.3V,   - Min: 3.0V,   - Max: 3.6V
| Library cells for typ/min/max conditions are connected as defined below:
|  IO - External Pad
|  A - Core Input
|  EN - Output Buffer Enable
|  BOOST - vdde
|  EHS - gnd
|  ENZI - vdd
|  EPD - gnd
|  EPUN - gnd
|  ZI - NC
|  ZIF - NC
|  gnd - gnd
|  gnde - gnde
|  vdd - vdd
|  vdde - vdde
| All other pins connected to ground
Model_type I/O
Polarity   Non-Inverting
Enable   Active-Low
Vinl =   0.9900V
Vinh =   2.3100V
Vmeas =  1.6500V
Cref =   0.0F
Rref =   100.0000
Vref =   0.0V
C_comp   1.5343pF   1.4580pF   1.6019pF
|C_comp_pullup   0.7259pF   0.7507pF   0.6892pF
|C_comp_pulldown   0.5955pF   0.6341pF   0.5597pF
[Model Spec]
| variable   typ   min   max
Vinh   0.9900V   0.9000V   1.0800V
Vinl   2.3100V   2.1000V   2.5200V
Vmeas   1.6500V   1.5000V   1.8000V
[Temperature Range]   25.0000   0.1250k   -40.0000
[Voltage Range]   3.3000V   3.0000V   3.6000V
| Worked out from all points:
|   slope of the pulldown table from 0 to 0.495 V, typ, clamps not added: 21 ohm
|   slope of the pullup table from 0 to 0.495 V, typ, clamps not added: 21.7 ohm
|   GND clamp passes 1 mA (typ) near -0.55 V on its own axis
|   POWER clamp passes 1 mA (typ) near -0.54 V on its own axis
|   rising waveform, R_fixture 50.0000, V_fixture 0.0: 20-80 % time 8.2ns typ, 12ns min, 5.45ns max; typ from 0.001 V to 2.21 V
|   rising waveform, R_fixture 50.0000, V_fixture 3.3000: 20-80 % time 151ps typ, 221ps min, 120ps max; typ from 1.12 V to 3.3 V
|   falling waveform, R_fixture 50.0000, V_fixture 0.0: 20-80 % time 179ps typ, 263ps min, 139ps max; typ from 2.21 V to 0.001 V
|   falling waveform, R_fixture 50.0000, V_fixture 3.3000: 20-80 % time 7.85ns typ, 11.2ns min, 5.22ns max; typ from 3.3 V to 1.12 V
[Pulldown]
|Voltage   I(typ)   I(min)   I(max)
-3.6V     -38.54mA   -26.03mA   -51.47mA
-1.29V    -29.27mA   -18.96mA   -40.78mA
-960mV    -36.81mA   -20.01mA   -53.83mA
-850mV    -38.18mA   -22.68mA   -52.4mA
-520mV    -27.12mA   -17.5mA    -37.74mA
580mV     26.98mA    16.83mA    38.78mA
1.35V     48.62mA    30.01mA    70.27mA
2.01V     54.62mA    33.69mA    78.71mA
4.43V     57.57mA    35.54mA    83.11mA
5.31V     62.85mA    38.64mA    90.87mA
6.3V      80.67mA    49.35mA    117.4mA
7.2V      112.3mA    68.85mA    163.6mA
[Pullup]
|Voltage   I(typ)   I(min)   I(max)
-3.6V     79.43mA    64.59mA    99.03mA
-1.05V    36.46mA    25.05mA    52.51mA
-830mV    38.41mA    22.29mA    50.98mA
-610mV    31.13mA    22.16mA    41.54mA
270mV     -13.03mA   -9.075mA   -18mA
710mV     -31.29mA   -21.6mA    -43.53mA
1.26V     -48.73mA   -33.16mA   -68.54mA
1.7V      -58.01mA   -38.97mA   -82.27mA
2.58V     -65.44mA   -43.49mA   -93.28mA
5.88V     -74.5mA    -49.46mA   -106.4mA
6.65V     -85.18mA   -56.54mA   -122.1mA
7.2V      -100.2mA   -66.51mA   -144.2mA
[GND_clamp]
|Voltage   I(typ)   I(min)   I(max)
-3.6V     -4.776A    -4.755A    -4.803A
-1.07V    -185.3mA   -255.8mA   -148mA
-960mV    -51.33mA   -111.9mA   -37.44mA
-850mV    -8.945mA   -25.5mA    -15.28mA
-740mV    -3.847mA   -5.583mA   -5.729mA
-630mV    -1.869mA   -1.835mA   -2.528mA
-520mV    -657.8uA   -634.6uA   -865.1uA
-300mV    -74.33uA   -64.35uA   -93.3uA
7.2V      0A         0A         0A
[POWER_clamp]
|Voltage   I(typ)   I(min)   I(max)
-3.6V     5.691A     5.665A     5.731A
-1.16V    387.4mA    485.6mA    339.2mA
-1.05V    187.8mA    295.9mA    142.7mA
-940mV    46.36mA    133mA      46.18mA
-830mV    9.713mA    34.98mA    20.13mA
-720mV    3.977mA    7.725mA    5.963mA
-610mV    1.851mA    2.026mA    2.529mA
-500mV    580.4uA    628.9uA    748uA
-280mV    7.181uA    13.64uA    7.137uA
7.2V      0A         0A         0A
[Ramp]
| variable   typ   min   max
dV/dt_r  1.3233/8.1978n   1.0166/11.9513n   1.6113/5.4489n
dV/dt_f  1.3105/7.8497n   0.9288/11.2342n   1.6253/5.2223n
R_load = 50.0000
[Rising Waveform]
R_fixture= 50.0000
V_fixture= 0.0
V_fixture_min= 0.0
V_fixture_max= 0.0
|time   V(typ)   V(min)   V(max)
0s        878.6uV    956.8uV    853.3uV
934.8ps   1.165mV    935.3uV    -55.59mV
2.14ns    1.232mV    -32.46mV   61.16mV
3.501ns   137.3mV    12.75mV    532.1mV
6.099ns   705.4mV    264.3mV    1.482V
9.052ns   1.271V     625.9mV    2.164V
14.72ns   1.871V     1.141V     2.534V
22.16ns   2.083V     1.472V     2.635V
32.99ns   2.168V     1.617V     2.673V
100ns     2.206V     1.695V     2.686V
[Rising Waveform]
R_fixture= 50.0000
V_fixture= 3.3000
V_fixture_min= 3.0000
V_fixture_max= 3.6000
|time   V(typ)   V(min)   V(max)
0s        1.116V     1.452V     891.1mV
777.6ps   1.116V     1.452V     984.2mV
840ps     1.116V     1.452V     1.328V
971.7ps   1.114V     1.452V     3.079V
1.156ns   1.187V     1.452V     3.534V
1.484ns   3.116V     1.45V      3.594V
1.817ns   3.289V     1.61V      3.596V
2.18ns    3.297V     2.871V     3.596V
2.692ns   3.297V     2.996V     3.596V
100ns     3.3V       3V         3.6V
[Falling Waveform]
R_fixture= 50.0000
V_fixture= 0.0
V_fixture_min= 0.0
V_fixture_max= 0.0
|time   V(typ)   V(min)   V(max)
0s        2.206V     1.696V     2.686V
799.6ps   2.206V     1.696V     2.587V
879ps     2.207V     1.696V     2.185V
1.011ns   2.206V     1.696V     609.6mV
1.136ns   2.131V     1.696V     136.4mV
1.537ns   140.1mV    1.694V     9.91mV
1.821ns   15.71mV    1.43V      6.911mV
2.208ns   5.798mV    133.4mV    6.659mV
2.677ns   5.465mV    7.331mV    4.777mV
100ns     878.6uV    956.9uV    853.3uV
[Falling Waveform]
R_fixture= 50.0000
V_fixture= 3.3000
V_fixture_min= 3.0000
V_fixture_max= 3.6000
|time   V(typ)   V(min)   V(max)
0s        3.3V       3V         3.6V
2.052ns   3.301V     3.037V     3.532V
3.178ns   3.184V     2.997V     3.103V
5.608ns   2.608V     2.763V     2.137V
7.849ns   2.14V      2.477V     1.545V
10.36ns   1.76V      2.209V     1.217V
14.2ns    1.435V     1.919V     1.031V
21.3ns    1.23V      1.646V     935.6mV
32.58ns   1.147V     1.513V     900.8mV
100ns     1.116V     1.452V     891.1mV
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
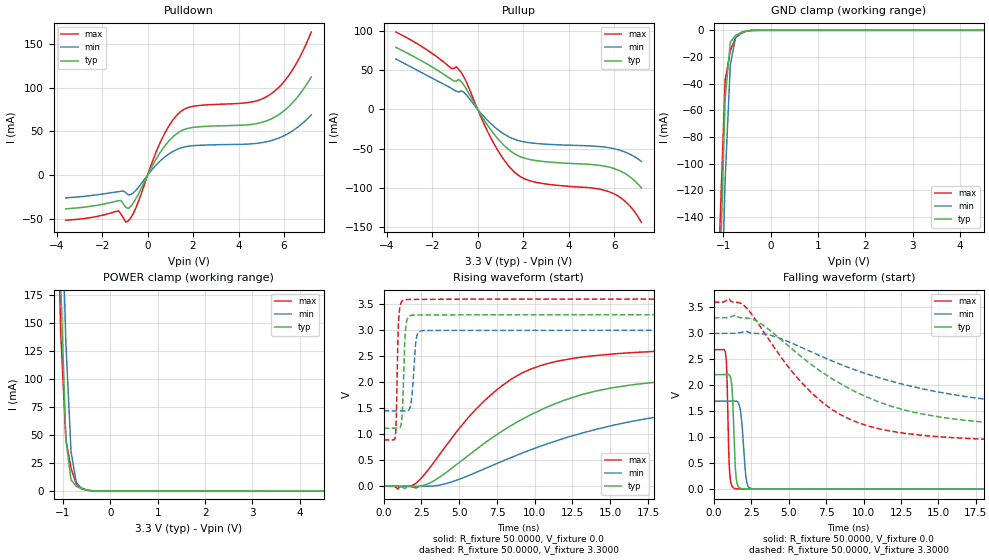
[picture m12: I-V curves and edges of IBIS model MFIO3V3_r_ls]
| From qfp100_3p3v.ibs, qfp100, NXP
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[Model] MFIO3V3_r_ls
|   Model MFIO3V3_r_ls
| This model was characterised for following simulation conditions:
| External (pad) voltage:
|   - Typ: 3.3V,   - Min: 3.0V,   - Max: 3.6V
| Library cells for typ/min/max conditions are connected as defined below:
|  IO - External Pad
|  A - Core Input
|  EN - Output Buffer Enable
|  BOOST - vdde
|  EHS - gnd
|  ENZI - vdd
|  EPD - vdd
|  EPUN - gnd
|  ZI - NC
|  ZIF - NC
|  gnd - gnd
|  gnde - gnde
|  vdd - vdd
|  vdde - vdde
| All other pins connected to ground
Model_type I/O
Polarity   Non-Inverting
Enable   Active-Low
Vinl =   0.9900V
Vinh =   2.3100V
Vmeas =  1.6500V
Cref =   0.0F
Rref =   100.0000
Vref =   0.0V
C_comp   1.5343pF   1.4580pF   1.6019pF
|C_comp_pullup   0.7283pF   0.7532pF   0.6914pF
|C_comp_pulldown   0.5932pF   0.6316pF   0.5575pF
[Model Spec]
| variable   typ   min   max
Vinh   0.9900V   0.9000V   1.0800V
Vinl   2.3100V   2.1000V   2.5200V
Vmeas   1.6500V   1.5000V   1.8000V
[Temperature Range]   25.0000   0.1250k   -40.0000
[Voltage Range]   3.3000V   3.0000V   3.6000V
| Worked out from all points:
|   slope of the pulldown table from 0 to 0.495 V, typ, clamps not added: 21 ohm
|   slope of the pullup table from 0 to 0.495 V, typ, clamps not added: 21.7 ohm
|   GND clamp passes 1 mA (typ) near -0.56 V on its own axis
|   POWER clamp passes 1 mA (typ) near -0.53 V on its own axis
|   rising waveform, R_fixture 50.0000, V_fixture 0.0: 20-80 % time 8.21ns typ, 11.9ns min, 5.46ns max; typ from 0 V to 2.21 V
|   rising waveform, R_fixture 50.0000, V_fixture 3.3000: 20-80 % time 151ps typ, 221ps min, 120ps max; typ from 1.11 V to 3.3 V
|   falling waveform, R_fixture 50.0000, V_fixture 0.0: 20-80 % time 179ps typ, 263ps min, 138ps max; typ from 2.21 V to 0 V
|   falling waveform, R_fixture 50.0000, V_fixture 3.3000: 20-80 % time 7.85ns typ, 11.2ns min, 5.22ns max; typ from 3.3 V to 1.11 V
[Pulldown]
|Voltage   I(typ)   I(min)   I(max)
-3.6V     -38.54mA   -26.03mA   -51.47mA
-1.29V    -29.27mA   -18.96mA   -40.78mA
-960mV    -36.81mA   -20.01mA   -53.83mA
-850mV    -38.18mA   -22.68mA   -52.4mA
-520mV    -27.12mA   -17.5mA    -37.74mA
580mV     26.98mA    16.83mA    38.78mA
1.35V     48.62mA    30.01mA    70.27mA
2.01V     54.62mA    33.69mA    78.71mA
4.43V     57.57mA    35.54mA    83.11mA
5.31V     62.85mA    38.63mA    90.87mA
6.3V      80.67mA    49.35mA    117.4mA
7.2V      112.3mA    68.85mA    163.6mA
[Pullup]
|Voltage   I(typ)   I(min)   I(max)
-3.6V     79.43mA    64.59mA    99.03mA
-1.05V    36.46mA    25.05mA    52.51mA
-830mV    38.41mA    22.29mA    50.98mA
-610mV    31.13mA    22.16mA    41.54mA
270mV     -13.03mA   -9.075mA   -18mA
710mV     -31.29mA   -21.6mA    -43.53mA
1.26V     -48.73mA   -33.16mA   -68.54mA
1.7V      -58.01mA   -38.97mA   -82.27mA
2.58V     -65.44mA   -43.49mA   -93.28mA
5.88V     -74.5mA    -49.46mA   -106.4mA
6.65V     -85.19mA   -56.54mA   -122.1mA
7.2V      -100.2mA   -66.51mA   -144.2mA
[GND_clamp]
|Voltage   I(typ)   I(min)   I(max)
-3.6V     -4.776A    -4.755A    -4.803A
-1.07V    -185.2mA   -255.8mA   -147.9mA
-960mV    -51.26mA   -111.8mA   -37.36mA
-850mV    -8.879mA   -25.45mA   -15.19mA
-740mV    -3.782mA   -5.531mA   -5.645mA
-630mV    -1.803mA   -1.784mA   -2.444mA
-520mV    -592.1uA   -582.6uA   -781uA
-300mV    -8.619uA   -12.3uA    -9.227uA
7.2V      0A         0A         0A
[POWER_clamp]
|Voltage   I(typ)   I(min)   I(max)
-3.6V     5.691A     5.665A     5.731A
-1.16V    387.4mA    485.6mA    339.3mA
-1.05V    187.9mA    295.9mA    142.8mA
-940mV    46.42mA    133mA      46.27mA
-830mV    9.779mA    35.03mA    20.21mA
-720mV    4.043mA    7.776mA    6.047mA
-610mV    1.916mA    2.078mA    2.613mA
-500mV    646.2uA    680.9uA    832.2uA
-280mV    73uA       65.71uA    91.35uA
7.2V      0A         0A         0A
[Ramp]
| variable   typ   min   max
dV/dt_r  1.3230/8.2134n   1.0163/11.9319n   1.6111/5.4554n
dV/dt_f  1.3109/7.8535n   0.9293/11.2287n   1.6255/5.2150n
R_load = 50.0000
[Rising Waveform]
R_fixture= 50.0000
V_fixture= 0.0
V_fixture_min= 0.0
V_fixture_max= 0.0
|time   V(typ)   V(min)   V(max)
0s        3.835nV    108.6nV    40.83nV
2.163ns   -1.964mV   -33.83mV   62.17mV
3.313ns   101mV      3.859mV    454mV
5.79ns    634.1mV    224mV      1.381V
8.437ns   1.165V     551mV      2.056V
10.84ns   1.524V     815.8mV    2.358V
14.87ns   1.877V     1.149V     2.536V
21.75ns   2.076V     1.46V      2.63V
34.37ns   2.171V     1.625V     2.674V
100ns     2.205V     1.694V     2.685V
[Rising Waveform]
R_fixture= 50.0000
V_fixture= 3.3000
V_fixture_min= 3.0000
V_fixture_max= 3.6000
|time   V(typ)   V(min)   V(max)
0s        1.114V     1.45V      889.8mV
780.5ps   1.114V     1.45V      989.8mV
842.1ps   1.114V     1.45V      1.347V
971.7ps   1.113V     1.45V      3.075V
1.149ns   1.176V     1.45V      3.525V
1.462ns   3.06V      1.448V     3.589V
1.821ns   3.286V     1.616V     3.592V
2.182ns   3.293V     2.871V     3.592V
2.673ns   3.294V     2.993V     3.593V
100ns     3.299V     2.999V     3.599V
[Falling Waveform]
R_fixture= 50.0000
V_fixture= 0.0
V_fixture_min= 0.0
V_fixture_max= 0.0
|time   V(typ)   V(min)   V(max)
0s        2.205V     1.694V     2.685V
805.7ps   2.205V     1.694V     2.572V
873.5ps   2.206V     1.694V     2.235V
1.017ns   2.204V     1.694V     561.4mV
1.141ns   2.123V     1.694V     124.8mV
1.552ns   117.3mV    1.691V     5.338mV
1.81ns    13.33mV    1.455V     2.765mV
2.192ns   2.598mV    152.8mV    2.892mV
2.701ns   2.274mV    4.294mV    1.961mV
100ns     23.69nV    181.1nV    46.63nV
[Falling Waveform]
R_fixture= 50.0000
V_fixture= 3.3000
V_fixture_min= 3.0000
V_fixture_max= 3.6000
|time   V(typ)   V(min)   V(max)
0s        3.299V     2.999V     3.599V
1.02ns    3.304V     2.999V     3.661V
2.062ns   3.298V     3.036V     3.526V
5.16ns    2.713V     2.817V     2.287V
7.883ns   2.129V     2.471V     1.535V
10.41ns   1.751V     2.201V     1.21V
14.28ns   1.429V     1.912V     1.027V
22.24ns   1.216V     1.625V     928.3mV
34.2ns    1.14V      1.502V     897.6mV
100ns     1.114V     1.45V      889.8mV
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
